One B-rep face of a CAD part: STEP entity #329.
In plain terms, the planar face has unit normal (0, 0, -1).
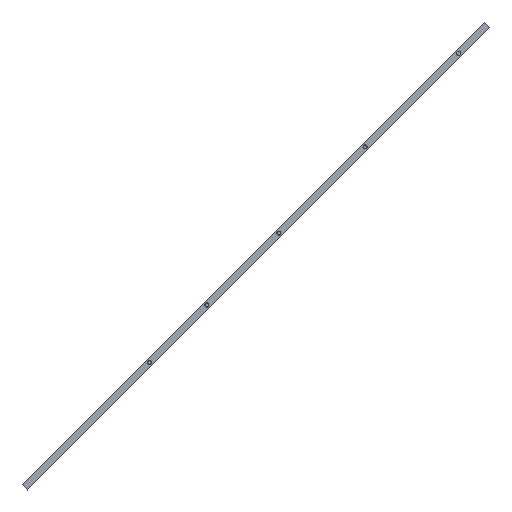
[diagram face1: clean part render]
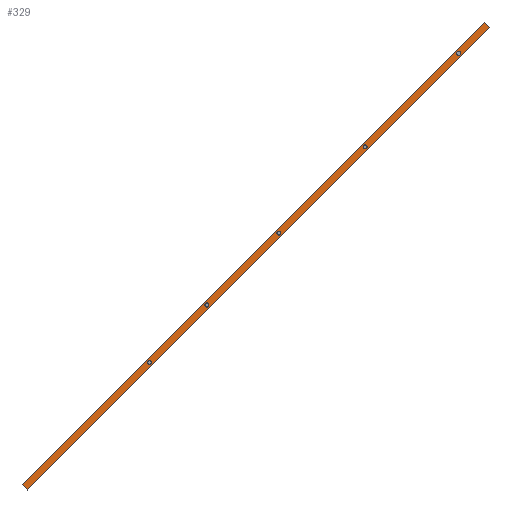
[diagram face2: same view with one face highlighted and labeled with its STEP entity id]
Its self-contained STEP definition (entity closure, numbers rounded to 3 decimals):
#40 = VERTEX_POINT('',#41);
#41 = CARTESIAN_POINT('',(189.8,-170.05,22.5));
#50 = PLANE('',#51);
#51 = AXIS2_PLACEMENT_3D('',#52,#53,#54);
#52 = CARTESIAN_POINT('',(189.8,-170.05,22.5));
#53 = DIRECTION('',(0.,1.,0.));
#54 = DIRECTION('',(0.,0.,1.));
#62 = PLANE('',#63);
#63 = AXIS2_PLACEMENT_3D('',#64,#65,#66);
#64 = CARTESIAN_POINT('',(189.8,-170.05,22.5));
#65 = DIRECTION('',(-1.,0.,0.));
#66 = DIRECTION('',(0.,0.,1.));
#74 = EDGE_CURVE('',#40,#75,#77,.T.);
#75 = VERTEX_POINT('',#76);
#76 = CARTESIAN_POINT('',(186.2,-170.05,22.5));
#77 = SURFACE_CURVE('',#78,(#82,#89),.PCURVE_S1.);
#78 = LINE('',#79,#80);
#79 = CARTESIAN_POINT('',(189.8,-170.05,22.5));
#80 = VECTOR('',#81,1.);
#81 = DIRECTION('',(-1.,0.,0.));
#82 = PCURVE('',#50,#83);
#83 = DEFINITIONAL_REPRESENTATION('',(#84),#88);
#84 = LINE('',#85,#86);
#85 = CARTESIAN_POINT('',(0.,0.));
#86 = VECTOR('',#87,1.);
#87 = DIRECTION('',(0.,-1.));
#88 = ( GEOMETRIC_REPRESENTATION_CONTEXT(2) 
PARAMETRIC_REPRESENTATION_CONTEXT() REPRESENTATION_CONTEXT('2D SPACE',''
  ) );
#89 = PCURVE('',#90,#95);
#90 = PLANE('',#91);
#91 = AXIS2_PLACEMENT_3D('',#92,#93,#94);
#92 = CARTESIAN_POINT('',(189.8,-170.05,22.5));
#93 = DIRECTION('',(0.,0.,1.));
#94 = DIRECTION('',(0.,1.,0.));
#95 = DEFINITIONAL_REPRESENTATION('',(#96),#100);
#96 = LINE('',#97,#98);
#97 = CARTESIAN_POINT('',(0.,0.));
#98 = VECTOR('',#99,1.);
#99 = DIRECTION('',(0.,1.));
#100 = ( GEOMETRIC_REPRESENTATION_CONTEXT(2) 
PARAMETRIC_REPRESENTATION_CONTEXT() REPRESENTATION_CONTEXT('2D SPACE',''
  ) );
#118 = PLANE('',#119);
#119 = AXIS2_PLACEMENT_3D('',#120,#121,#122);
#120 = CARTESIAN_POINT('',(186.2,-170.05,22.5));
#121 = DIRECTION('',(-1.,0.,0.));
#122 = DIRECTION('',(0.,0.,1.));
#159 = EDGE_CURVE('',#40,#160,#162,.T.);
#160 = VERTEX_POINT('',#161);
#161 = CARTESIAN_POINT('',(189.8,151.85,22.5));
#162 = SURFACE_CURVE('',#163,(#167,#174),.PCURVE_S1.);
#163 = LINE('',#164,#165);
#164 = CARTESIAN_POINT('',(189.8,-170.05,22.5));
#165 = VECTOR('',#166,1.);
#166 = DIRECTION('',(0.,1.,0.));
#167 = PCURVE('',#62,#168);
#168 = DEFINITIONAL_REPRESENTATION('',(#169),#173);
#169 = LINE('',#170,#171);
#170 = CARTESIAN_POINT('',(0.,0.));
#171 = VECTOR('',#172,1.);
#172 = DIRECTION('',(0.,1.));
#173 = ( GEOMETRIC_REPRESENTATION_CONTEXT(2) 
PARAMETRIC_REPRESENTATION_CONTEXT() REPRESENTATION_CONTEXT('2D SPACE',''
  ) );
#174 = PCURVE('',#90,#175);
#175 = DEFINITIONAL_REPRESENTATION('',(#176),#180);
#176 = LINE('',#177,#178);
#177 = CARTESIAN_POINT('',(0.,0.));
#178 = VECTOR('',#179,1.);
#179 = DIRECTION('',(1.,0.));
#180 = ( GEOMETRIC_REPRESENTATION_CONTEXT(2) 
PARAMETRIC_REPRESENTATION_CONTEXT() REPRESENTATION_CONTEXT('2D SPACE',''
  ) );
#220 = PLANE('',#221);
#221 = AXIS2_PLACEMENT_3D('',#222,#223,#224);
#222 = CARTESIAN_POINT('',(189.8,151.85,22.5));
#223 = DIRECTION('',(0.,1.,0.));
#224 = DIRECTION('',(0.,0.,1.));
#284 = EDGE_CURVE('',#75,#285,#287,.T.);
#285 = VERTEX_POINT('',#286);
#286 = CARTESIAN_POINT('',(186.2,151.85,22.5));
#287 = SURFACE_CURVE('',#288,(#292,#299),.PCURVE_S1.);
#288 = LINE('',#289,#290);
#289 = CARTESIAN_POINT('',(186.2,-170.05,22.5));
#290 = VECTOR('',#291,1.);
#291 = DIRECTION('',(0.,1.,0.));
#292 = PCURVE('',#118,#293);
#293 = DEFINITIONAL_REPRESENTATION('',(#294),#298);
#294 = LINE('',#295,#296);
#295 = CARTESIAN_POINT('',(0.,0.));
#296 = VECTOR('',#297,1.);
#297 = DIRECTION('',(0.,1.));
#298 = ( GEOMETRIC_REPRESENTATION_CONTEXT(2) 
PARAMETRIC_REPRESENTATION_CONTEXT() REPRESENTATION_CONTEXT('2D SPACE',''
  ) );
#299 = PCURVE('',#90,#300);
#300 = DEFINITIONAL_REPRESENTATION('',(#301),#305);
#301 = LINE('',#302,#303);
#302 = CARTESIAN_POINT('',(0.,3.6));
#303 = VECTOR('',#304,1.);
#304 = DIRECTION('',(1.,0.));
#305 = ( GEOMETRIC_REPRESENTATION_CONTEXT(2) 
PARAMETRIC_REPRESENTATION_CONTEXT() REPRESENTATION_CONTEXT('2D SPACE',''
  ) );
#329 = ADVANCED_FACE('',(#330,#356,#387,#418,#449,#480),#90,.F.);
#330 = FACE_BOUND('',#331,.F.);
#331 = EDGE_LOOP('',(#332,#333,#334,#355));
#332 = ORIENTED_EDGE('',*,*,#74,.F.);
#333 = ORIENTED_EDGE('',*,*,#159,.T.);
#334 = ORIENTED_EDGE('',*,*,#335,.T.);
#335 = EDGE_CURVE('',#160,#285,#336,.T.);
#336 = SURFACE_CURVE('',#337,(#341,#348),.PCURVE_S1.);
#337 = LINE('',#338,#339);
#338 = CARTESIAN_POINT('',(189.8,151.85,22.5));
#339 = VECTOR('',#340,1.);
#340 = DIRECTION('',(-1.,0.,0.));
#341 = PCURVE('',#90,#342);
#342 = DEFINITIONAL_REPRESENTATION('',(#343),#347);
#343 = LINE('',#344,#345);
#344 = CARTESIAN_POINT('',(321.9,0.));
#345 = VECTOR('',#346,1.);
#346 = DIRECTION('',(0.,1.));
#347 = ( GEOMETRIC_REPRESENTATION_CONTEXT(2) 
PARAMETRIC_REPRESENTATION_CONTEXT() REPRESENTATION_CONTEXT('2D SPACE',''
  ) );
#348 = PCURVE('',#220,#349);
#349 = DEFINITIONAL_REPRESENTATION('',(#350),#354);
#350 = LINE('',#351,#352);
#351 = CARTESIAN_POINT('',(0.,0.));
#352 = VECTOR('',#353,1.);
#353 = DIRECTION('',(0.,-1.));
#354 = ( GEOMETRIC_REPRESENTATION_CONTEXT(2) 
PARAMETRIC_REPRESENTATION_CONTEXT() REPRESENTATION_CONTEXT('2D SPACE',''
  ) );
#355 = ORIENTED_EDGE('',*,*,#284,.F.);
#356 = FACE_BOUND('',#357,.F.);
#357 = EDGE_LOOP('',(#358));
#358 = ORIENTED_EDGE('',*,*,#359,.F.);
#359 = EDGE_CURVE('',#360,#360,#362,.T.);
#360 = VERTEX_POINT('',#361);
#361 = CARTESIAN_POINT('',(189.,-150.,22.5));
#362 = SURFACE_CURVE('',#363,(#368,#375),.PCURVE_S1.);
#363 = CIRCLE('',#364,1.);
#364 = AXIS2_PLACEMENT_3D('',#365,#366,#367);
#365 = CARTESIAN_POINT('',(188.,-150.,22.5));
#366 = DIRECTION('',(0.,0.,1.));
#367 = DIRECTION('',(1.,0.,-0.));
#368 = PCURVE('',#90,#369);
#369 = DEFINITIONAL_REPRESENTATION('',(#370),#374);
#370 = CIRCLE('',#371,1.);
#371 = AXIS2_PLACEMENT_2D('',#372,#373);
#372 = CARTESIAN_POINT('',(20.05,1.8));
#373 = DIRECTION('',(0.,-1.));
#374 = ( GEOMETRIC_REPRESENTATION_CONTEXT(2) 
PARAMETRIC_REPRESENTATION_CONTEXT() REPRESENTATION_CONTEXT('2D SPACE',''
  ) );
#375 = PCURVE('',#376,#381);
#376 = CYLINDRICAL_SURFACE('',#377,1.);
#377 = AXIS2_PLACEMENT_3D('',#378,#379,#380);
#378 = CARTESIAN_POINT('',(188.,-150.,21.7));
#379 = DIRECTION('',(0.,0.,1.));
#380 = DIRECTION('',(1.,0.,-0.));
#381 = DEFINITIONAL_REPRESENTATION('',(#382),#386);
#382 = LINE('',#383,#384);
#383 = CARTESIAN_POINT('',(0.,0.8));
#384 = VECTOR('',#385,1.);
#385 = DIRECTION('',(1.,0.));
#386 = ( GEOMETRIC_REPRESENTATION_CONTEXT(2) 
PARAMETRIC_REPRESENTATION_CONTEXT() REPRESENTATION_CONTEXT('2D SPACE',''
  ) );
#387 = FACE_BOUND('',#388,.F.);
#388 = EDGE_LOOP('',(#389));
#389 = ORIENTED_EDGE('',*,*,#390,.F.);
#390 = EDGE_CURVE('',#391,#391,#393,.T.);
#391 = VERTEX_POINT('',#392);
#392 = CARTESIAN_POINT('',(189.,-85.,22.5));
#393 = SURFACE_CURVE('',#394,(#399,#406),.PCURVE_S1.);
#394 = CIRCLE('',#395,1.);
#395 = AXIS2_PLACEMENT_3D('',#396,#397,#398);
#396 = CARTESIAN_POINT('',(188.,-85.,22.5));
#397 = DIRECTION('',(0.,0.,1.));
#398 = DIRECTION('',(1.,0.,-0.));
#399 = PCURVE('',#90,#400);
#400 = DEFINITIONAL_REPRESENTATION('',(#401),#405);
#401 = CIRCLE('',#402,1.);
#402 = AXIS2_PLACEMENT_2D('',#403,#404);
#403 = CARTESIAN_POINT('',(85.05,1.8));
#404 = DIRECTION('',(0.,-1.));
#405 = ( GEOMETRIC_REPRESENTATION_CONTEXT(2) 
PARAMETRIC_REPRESENTATION_CONTEXT() REPRESENTATION_CONTEXT('2D SPACE',''
  ) );
#406 = PCURVE('',#407,#412);
#407 = CYLINDRICAL_SURFACE('',#408,1.);
#408 = AXIS2_PLACEMENT_3D('',#409,#410,#411);
#409 = CARTESIAN_POINT('',(188.,-85.,21.7));
#410 = DIRECTION('',(0.,0.,1.));
#411 = DIRECTION('',(1.,0.,-0.));
#412 = DEFINITIONAL_REPRESENTATION('',(#413),#417);
#413 = LINE('',#414,#415);
#414 = CARTESIAN_POINT('',(0.,0.8));
#415 = VECTOR('',#416,1.);
#416 = DIRECTION('',(1.,0.));
#417 = ( GEOMETRIC_REPRESENTATION_CONTEXT(2) 
PARAMETRIC_REPRESENTATION_CONTEXT() REPRESENTATION_CONTEXT('2D SPACE',''
  ) );
#418 = FACE_BOUND('',#419,.F.);
#419 = EDGE_LOOP('',(#420));
#420 = ORIENTED_EDGE('',*,*,#421,.F.);
#421 = EDGE_CURVE('',#422,#422,#424,.T.);
#422 = VERTEX_POINT('',#423);
#423 = CARTESIAN_POINT('',(189.,-25.,22.5));
#424 = SURFACE_CURVE('',#425,(#430,#437),.PCURVE_S1.);
#425 = CIRCLE('',#426,1.);
#426 = AXIS2_PLACEMENT_3D('',#427,#428,#429);
#427 = CARTESIAN_POINT('',(188.,-25.,22.5));
#428 = DIRECTION('',(0.,0.,1.));
#429 = DIRECTION('',(1.,0.,-0.));
#430 = PCURVE('',#90,#431);
#431 = DEFINITIONAL_REPRESENTATION('',(#432),#436);
#432 = CIRCLE('',#433,1.);
#433 = AXIS2_PLACEMENT_2D('',#434,#435);
#434 = CARTESIAN_POINT('',(145.05,1.8));
#435 = DIRECTION('',(0.,-1.));
#436 = ( GEOMETRIC_REPRESENTATION_CONTEXT(2) 
PARAMETRIC_REPRESENTATION_CONTEXT() REPRESENTATION_CONTEXT('2D SPACE',''
  ) );
#437 = PCURVE('',#438,#443);
#438 = CYLINDRICAL_SURFACE('',#439,1.);
#439 = AXIS2_PLACEMENT_3D('',#440,#441,#442);
#440 = CARTESIAN_POINT('',(188.,-25.,21.7));
#441 = DIRECTION('',(0.,0.,1.));
#442 = DIRECTION('',(1.,0.,-0.));
#443 = DEFINITIONAL_REPRESENTATION('',(#444),#448);
#444 = LINE('',#445,#446);
#445 = CARTESIAN_POINT('',(0.,0.8));
#446 = VECTOR('',#447,1.);
#447 = DIRECTION('',(1.,0.));
#448 = ( GEOMETRIC_REPRESENTATION_CONTEXT(2) 
PARAMETRIC_REPRESENTATION_CONTEXT() REPRESENTATION_CONTEXT('2D SPACE',''
  ) );
#449 = FACE_BOUND('',#450,.F.);
#450 = EDGE_LOOP('',(#451));
#451 = ORIENTED_EDGE('',*,*,#452,.F.);
#452 = EDGE_CURVE('',#453,#453,#455,.T.);
#453 = VERTEX_POINT('',#454);
#454 = CARTESIAN_POINT('',(189.,25.,22.5));
#455 = SURFACE_CURVE('',#456,(#461,#468),.PCURVE_S1.);
#456 = CIRCLE('',#457,1.);
#457 = AXIS2_PLACEMENT_3D('',#458,#459,#460);
#458 = CARTESIAN_POINT('',(188.,25.,22.5));
#459 = DIRECTION('',(0.,0.,1.));
#460 = DIRECTION('',(1.,0.,-0.));
#461 = PCURVE('',#90,#462);
#462 = DEFINITIONAL_REPRESENTATION('',(#463),#467);
#463 = CIRCLE('',#464,1.);
#464 = AXIS2_PLACEMENT_2D('',#465,#466);
#465 = CARTESIAN_POINT('',(195.05,1.8));
#466 = DIRECTION('',(0.,-1.));
#467 = ( GEOMETRIC_REPRESENTATION_CONTEXT(2) 
PARAMETRIC_REPRESENTATION_CONTEXT() REPRESENTATION_CONTEXT('2D SPACE',''
  ) );
#468 = PCURVE('',#469,#474);
#469 = CYLINDRICAL_SURFACE('',#470,1.);
#470 = AXIS2_PLACEMENT_3D('',#471,#472,#473);
#471 = CARTESIAN_POINT('',(188.,25.,21.7));
#472 = DIRECTION('',(0.,0.,1.));
#473 = DIRECTION('',(1.,0.,-0.));
#474 = DEFINITIONAL_REPRESENTATION('',(#475),#479);
#475 = LINE('',#476,#477);
#476 = CARTESIAN_POINT('',(0.,0.8));
#477 = VECTOR('',#478,1.);
#478 = DIRECTION('',(1.,0.));
#479 = ( GEOMETRIC_REPRESENTATION_CONTEXT(2) 
PARAMETRIC_REPRESENTATION_CONTEXT() REPRESENTATION_CONTEXT('2D SPACE',''
  ) );
#480 = FACE_BOUND('',#481,.F.);
#481 = EDGE_LOOP('',(#482));
#482 = ORIENTED_EDGE('',*,*,#483,.F.);
#483 = EDGE_CURVE('',#484,#484,#486,.T.);
#484 = VERTEX_POINT('',#485);
#485 = CARTESIAN_POINT('',(189.,65.,22.5));
#486 = SURFACE_CURVE('',#487,(#492,#499),.PCURVE_S1.);
#487 = CIRCLE('',#488,1.);
#488 = AXIS2_PLACEMENT_3D('',#489,#490,#491);
#489 = CARTESIAN_POINT('',(188.,65.,22.5));
#490 = DIRECTION('',(0.,0.,1.));
#491 = DIRECTION('',(1.,0.,-0.));
#492 = PCURVE('',#90,#493);
#493 = DEFINITIONAL_REPRESENTATION('',(#494),#498);
#494 = CIRCLE('',#495,1.);
#495 = AXIS2_PLACEMENT_2D('',#496,#497);
#496 = CARTESIAN_POINT('',(235.05,1.8));
#497 = DIRECTION('',(0.,-1.));
#498 = ( GEOMETRIC_REPRESENTATION_CONTEXT(2) 
PARAMETRIC_REPRESENTATION_CONTEXT() REPRESENTATION_CONTEXT('2D SPACE',''
  ) );
#499 = PCURVE('',#500,#505);
#500 = CYLINDRICAL_SURFACE('',#501,1.);
#501 = AXIS2_PLACEMENT_3D('',#502,#503,#504);
#502 = CARTESIAN_POINT('',(188.,65.,21.7));
#503 = DIRECTION('',(0.,0.,1.));
#504 = DIRECTION('',(1.,0.,-0.));
#505 = DEFINITIONAL_REPRESENTATION('',(#506),#510);
#506 = LINE('',#507,#508);
#507 = CARTESIAN_POINT('',(0.,0.8));
#508 = VECTOR('',#509,1.);
#509 = DIRECTION('',(1.,0.));
#510 = ( GEOMETRIC_REPRESENTATION_CONTEXT(2) 
PARAMETRIC_REPRESENTATION_CONTEXT() REPRESENTATION_CONTEXT('2D SPACE',''
  ) );
